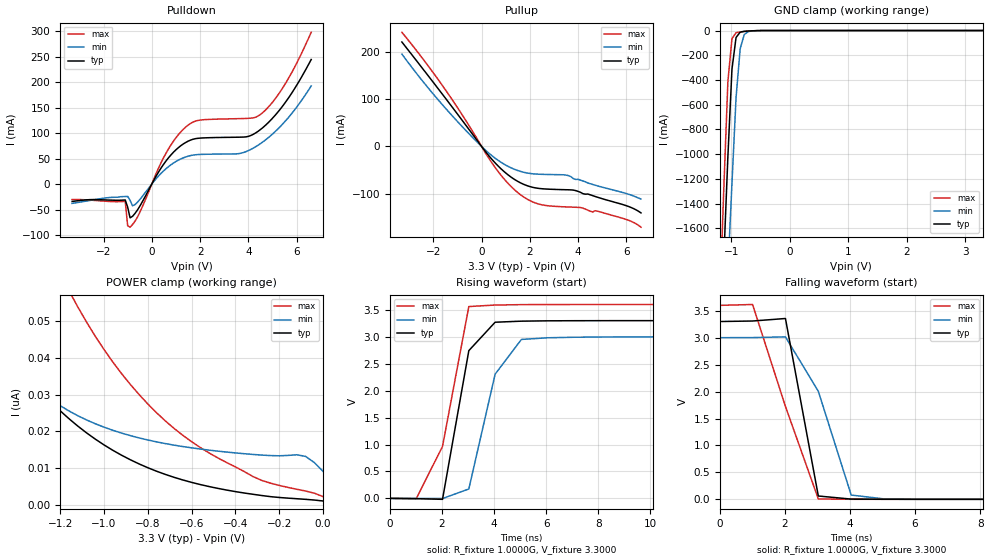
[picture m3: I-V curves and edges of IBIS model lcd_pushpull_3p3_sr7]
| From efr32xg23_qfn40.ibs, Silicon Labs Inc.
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|   Model lcd_pushpull_3p3_sr7
[Model]  lcd_pushpull_3p3_sr7
Model_type 3-state
Polarity   Non-Inverting
Enable   Active-High
C_comp   1.6300pF   1.4000pF   2.7000pF
[Temperature Range]   25.0000   0.1250k   -40.0000
[Pullup Reference]   3.3000V   3.0000V   3.6000V
[Pulldown Reference]   0.0V   0.0V   0.0V
[POWER Clamp Reference]   3.3000V   3.0000V   3.6000V
[GND Clamp Reference]   0.0V   0.0V   0.0V
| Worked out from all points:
|   slope of the pulldown table from 0 to 0.495 V, typ, clamps not added: 12.6 ohm
|   slope of the pullup table from 0 to 0.495 V, typ, clamps not added: 15.9 ohm
|   GND clamp passes 1 mA (typ) near -0.56 V on its own axis
|   rising waveform, R_fixture 1.0000G, V_fixture 3.3000: 20-80 % time 724ps typ, 955ps min, 1ns max; typ from 0 V to 3.3 V
|   falling waveform, R_fixture 1.0000G, V_fixture 3.3000: 20-80 % time 607ps typ, 1.13ns min, 1.21ns max; typ from 3.3 V to 0 V
[Pulldown]
|Voltage   I(typ)   I(min)   I(max)
-3.3V     -34.2mA    -37.99mA   -30.45mA
-1.1V     -31.33mA   -24.53mA   -34.17mA
-1V       -45.32mA   -24.25mA   -81.91mA
-900mV    -66.33mA   -32.01mA   -84.65mA
-700mV    -57.95mA   -40.56mA   -73.32mA
500mV     39.57mA    26.37mA    52.76mA
1.2V      75.23mA    49.28mA    102.4mA
1.9V      89.73mA    57.85mA    124.8mA
3.6V      92mA       59.71mA    128.4mA
4.5V      107.1mA    79.43mA    136.7mA
5.5V      158.4mA    122.1mA    194.8mA
6.6V      244.5mA    192.6mA    297.9mA
[Pullup]
|Voltage   I(typ)   I(min)   I(max)
-3.3V     221.2mA    195.6mA    241.7mA
-1.7V     115.8mA    92.91mA    134.7mA
-200mV    13.9mA     10.19mA    17.6mA
200mV     -13.41mA   -9.668mA   -17.24mA
700mV     -42.19mA   -29.99mA   -54.16mA
1.5V      -74.1mA    -51.07mA   -97.84mA
1.9V      -83.4mA    -56.39mA   -112mA
2.4V      -89.1mA    -58.9mA    -122.5mA
3.6V      -91.86mA   -61.88mA   -128.3mA
4.9V      -109.2mA   -84.97mA   -138.5mA
6.1V      -127.5mA   -101.5mA   -156.7mA
6.6V      -140.8mA   -111.3mA   -171mA
[GND_clamp]
|Voltage   I(typ)   I(min)   I(max)
-3.3V     -27.87A    -25.05A    -30.64A
-1.2V     -2.686A    -3.389A    -2.22A
-1.13V    -1.852A    -2.669A    -1.282A
-1.06V    -1.021A    -1.951A    -413.8mA
-990mV    -311.8mA   -1.235A    -64.72mA
-920mV    -56.25mA   -542.5mA   -17.8mA
-850mV    -13.45mA   -148.5mA   -11.08mA
-780mV    -6.591mA   -32.68mA   -7.457mA
-710mV    -4.029mA   -8.323mA   -4.574mA
-360mV    -18.91uA   -70.05uA   -6.844uA
3.3V      1.07nA     13.64nA    781.9pA
[POWER_clamp]
|Voltage   I(typ)   I(min)   I(max)
-3.28V    727.8nA    32.99uA    1.086uA
-1.6V     57.64nA    55.61nA    128.6nA
-1.56V    53.42nA    50.92nA    120.3nA
-1.4V     38.98nA    37.13nA    91.2nA
-1.16V    23.46nA    25.56nA    58.31nA
-1.12V    21.47nA    24.28nA    53.91nA
-880mV    12.29nA    18.85nA    32.79nA
-640mV    6.783nA    15.87nA    18.92nA
-320mV    2.894nA    13.73nA    7.713nA
-120mV    1.684nA    13.64nA    4.257nA
-80mV     1.52nA     13.19nA    3.779nA
0V        1.07nA     9.091nA    2.25nA
[Ramp]
| variable   typ   min   max
dV/dt_r  1.9770/0.7286n   1.7963/0.9806n   2.1574/0.9973n
dV/dt_f  1.9778/0.6079n   1.7971/1.1326n   2.1582/1.2079n
R_load = 10.0000k
[Rising Waveform]
R_fixture= 1.0000G
V_fixture= 3.3000
V_fixture_min= 3.0000
V_fixture_max= 3.6000
|time   V(typ)   V(min)   V(max)
0s        2.697uV    5.542uV    1.599uV
1.01ns    -5.312mV   -1.811mV   -5.517mV
2.02ns    -17.79mV   -2.837mV   965.3mV
3.03ns    2.743V     174.4mV    3.562V
4.04ns    3.271V     2.307V     3.59V
5.051ns   3.291V     2.951V     3.598V
6.061ns   3.297V     2.982V     3.599V
12.12ns   3.3V       3V         3.6V
100ns     3.3V       3V         3.6V
[Falling Waveform]
R_fixture= 1.0000G
V_fixture= 3.3000
V_fixture_min= 3.0000
V_fixture_max= 3.6000
|time   V(typ)   V(min)   V(max)
0s        3.3V       3V         3.6V
1.01ns    3.309V     3.002V     3.616V
2.02ns    3.356V     3.015V     1.724V
3.03ns    61.74mV    2.005V     6.591mV
4.04ns    4.368mV    79.39mV    1.023mV
5.051ns   1.142mV    8.163mV    253.1uV
100ns     2.749uV    5.589uV    1.558uV
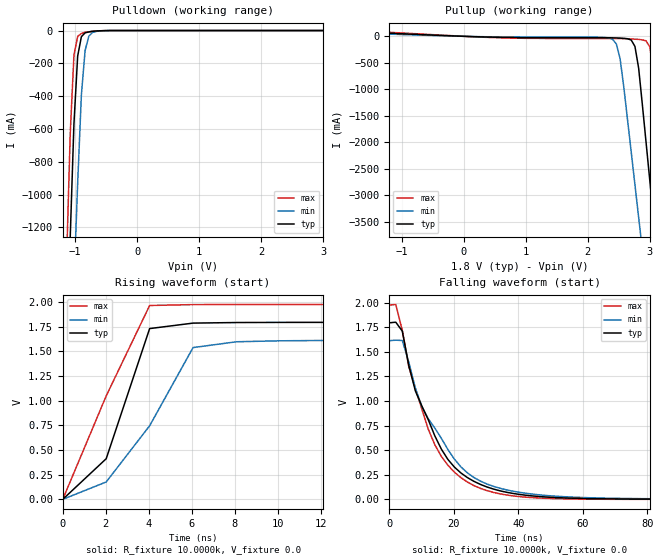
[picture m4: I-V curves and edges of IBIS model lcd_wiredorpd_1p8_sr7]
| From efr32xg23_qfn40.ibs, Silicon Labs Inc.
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|   Model lcd_wiredorpd_1p8_sr7
[Model]  lcd_wiredorpd_1p8_sr7
Model_type Output
Polarity   Non-Inverting
Enable   Active-Low
C_comp   1.6300pF   1.4000pF   2.7000pF
[Temperature Range]   25.0000   0.1250k   -40.0000
[Pullup Reference]   1.8000V   1.6200V   1.9800V
[Pulldown Reference]   0.0V   0.0V   0.0V
[POWER Clamp Reference]   1.8000V   1.6200V   1.9800V
[GND Clamp Reference]   0.0V   0.0V   0.0V
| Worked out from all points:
|   slope of the pulldown table from 0 to 0.27 V, typ, clamps not added: 40.6 kohm
|   slope of the pullup table from 0 to 0.27 V, typ, clamps not added: 26.3 ohm
|   rising waveform, R_fixture 10.0000k, V_fixture 0.0: 20-80 % time 1.83ns typ, 2.89ns min, 2.43ns max; typ from 0 V to 1.79 V
|   falling waveform, R_fixture 10.0000k, V_fixture 0.0: 20-80 % time 13.7ns typ, 15.6ns min, 12.3ns max; typ from 1.8 V to 0 V
[Pulldown]
|Voltage   I(typ)   I(min)   I(max)
-1.8V     -9.867A    -9.569A    -10.32A
-1.14V    -1.973A    -2.773A    -1.419A
-1.08V    -1.26A     -2.157A    -630.5mA
-1.02V    -568mA     -1.543A    -149.7mA
-960mV    -155.8mA   -930mA     -35.75mA
-900mV    -37.31mA   -392mA     -18.18mA
-840mV    -13.93mA   -121.5mA   -10.47mA
-780mV    -8.737mA   -34.04mA   -7.436mA
-720mV    -4.306mA   -11.22mA   -4.934mA
-660mV    -2.722mA   -5.276mA   -2.953mA
-360mV    -27.29uA   -76.51uA   -16.82uA
3.6V      88.26uA    75.14uA    103.4uA
[Pullup]
|Voltage   I(typ)   I(min)   I(max)
-1.8V     89.55mA    65.7mA     113.4mA
2.4V      -28.8mA    -55.09mA   -41.35mA
2.52V     -33.4mA    -414.8mA   -42.59mA
2.76V     -189.9mA   -2.797A    -53.83mA
2.82V     -601mA     -3.414A    -58.12mA
2.94V     -2.006A    -4.65A     -85.78mA
3V        -2.722A    -5.268A    -200.1mA
3.06V     -3.439A    -5.887A    -678.6mA
3.12V     -4.156A    -6.505A    -1.467A
3.24V     -5.593A    -7.743A    -3.079A
3.3V      -6.312A    -8.362A    -3.888A
3.6V      -9.909A    -11.46A    -7.94A
[Ramp]
| variable   typ   min   max
dV/dt_r  1.0772/1.8269n   0.9682/2.8879n   1.1859/2.4307n
dV/dt_f  0.2131/8.5780n   0.1690/11.9028n   0.2652/6.8020n
R_load = 10.0000k
[Rising Waveform]
R_fixture= 10.0000k
V_fixture= 0.0
V_fixture_min= 0.0
V_fixture_max= 0.0
|time   V(typ)   V(min)   V(max)
0s        2.578uV    44.87uV    2.149uV
2.02ns    412mV      176.1mV    1.049V
4.04ns    1.732V     746.3mV    1.966V
6.061ns   1.788V     1.539V     1.975V
8.081ns   1.794V     1.599V     1.976V
10.1ns    1.795V     1.608V     1.976V
200ns     1.795V     1.614V     1.976V
[Falling Waveform]
R_fixture= 10.0000k
V_fixture= 0.0
V_fixture_min= 0.0
V_fixture_max= 0.0
|time   V(typ)   V(min)   V(max)
0s        1.796V     1.614V     1.977V
2.02ns    1.802V     1.619V     1.982V
4.04ns    1.712V     1.616V     1.721V
6.061ns   1.361V     1.396V     1.349V
8.081ns   1.105V     1.133V     1.13V
14.14ns   644.4mV    723.6mV    553.7mV
20.2ns    327.2mV    407.9mV    275.7mV
30.3ns    124.8mV    154.8mV    87.6mV
62.63ns   6.153mV    14.65mV    516.5uV
200ns     -87.28uV   581.6uV    -354.3uV
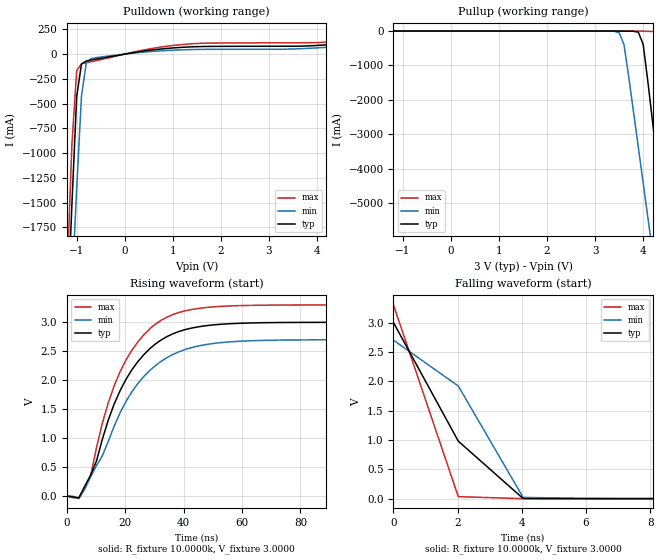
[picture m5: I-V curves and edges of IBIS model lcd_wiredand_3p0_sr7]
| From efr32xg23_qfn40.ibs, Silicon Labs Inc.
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|   Model lcd_wiredand_3p0_sr7
[Model]  lcd_wiredand_3p0_sr7
Model_type Output
Polarity   Inverting
Enable   Active-Low
C_comp   1.6300pF   1.4000pF   2.7000pF
[Temperature Range]   25.0000   0.1250k   -40.0000
[Pullup Reference]   3.0000V   2.7000V   3.3000V
[Pulldown Reference]   0.0V   0.0V   0.0V
[POWER Clamp Reference]   3.0000V   2.7000V   3.3000V
[GND Clamp Reference]   0.0V   0.0V   0.0V
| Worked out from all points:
|   slope of the pulldown table from 0 to 0.45 V, typ, clamps not added: 13.2 ohm
|   rising waveform, R_fixture 10.0000k, V_fixture 3.0000: 20-80 % time 15.6ns typ, 17.9ns min, 14.6ns max; typ from 0.003 V to 3 V
|   falling waveform, R_fixture 10.0000k, V_fixture 3.0000: 20-80 % time 2.2ns typ, 2.09ns min, 1.23ns max; typ from 3 V to 0.003 V
[Pulldown]
|Voltage   I(typ)   I(min)   I(max)
-3V       -24.3A     -21.99A    -26.6A
-1.2V     -2.716A    -3.412A    -2.254A
-1.1V     -1.526A    -2.385A    -915.6mA
-1V       -429.7mA   -1.36A     -165.3mA
-900mV    -99.37mA   -421mA     -98.78mA
-800mV    -69.26mA   -90.62mA   -87.32mA
-700mV    -59.97mA   -45.41mA   -76.82mA
400mV     30.95mA    19.99mA    42.35mA
1.1V      65.5mA     41.43mA    91.79mA
4.2V      93.5mA     68.54mA    121.5mA
5.1V      135.6mA    103.8mA    168.6mA
6V        196.8mA    153.8mA    241.9mA
[Pullup]
|Voltage   I(typ)   I(min)   I(max)
-3V       338.2nA    9.289uA    587.2nA
3.5V      -430.7uA   -50.4mA    -8.469nA
3.6V      -1.559mA   -390.7mA   -692.6nA
4V        -385.8mA   -4.417A    -4.219mA
4.1V      -1.495A    -5.446A    -8.403mA
4.2V      -2.686A    -6.476A    -14.95mA
4.3V      -3.882A    -7.507A    -84.19mA
4.4V      -5.077A    -8.538A    -881.8mA
4.5V      -6.274A    -9.569A    -2.22A
4.7V      -8.669A    -11.63A    -4.917A
4.8V      -9.867A    -12.66A    -6.266A
6V        -24.27A    -25.05A    -22.51A
[Ramp]
| variable   typ   min   max
dV/dt_r  -0.1715m/16.5924p   -0.1952m/52.2320p   -0.1327m/7.4384p
dV/dt_f  1.7980/2.2050n   1.6171/2.0910n   1.9783/1.2251n
R_load = 10.0000k
[Rising Waveform]
R_fixture= 10.0000k
V_fixture= 3.0000
V_fixture_min= 2.7000
V_fixture_max= 3.3000
|time   V(typ)   V(min)   V(max)
0s        3.394mV    4.689mV    2.757mV
4.04ns    -26.64mV   -43.13mV   -32.57mV
8.081ns   361.7mV    335.4mV    354.1mV
14.14ns   1.316V     949.2mV    1.614V
18.18ns   1.821V     1.441V     2.148V
22.22ns   2.182V     1.801V     2.519V
30.3ns    2.627V     2.254V     2.97V
38.38ns   2.842V     2.493V     3.17V
66.67ns   2.992V     2.687V     3.295V
200ns     3V         2.7V       3.3V
[Falling Waveform]
R_fixture= 10.0000k
V_fixture= 3.0000
V_fixture_min= 2.7000
V_fixture_max= 3.3000
|time   V(typ)   V(min)   V(max)
0s        3V         2.7V       3.3V
2.02ns    981.8mV    1.92V      37.65mV
4.04ns    5.833mV    24.8mV     3.331mV
6.061ns   3.703mV    6.836mV    2.832mV
10.1ns    3.446mV    4.884mV    2.783mV
200ns     3.395mV    4.692mV    2.758mV
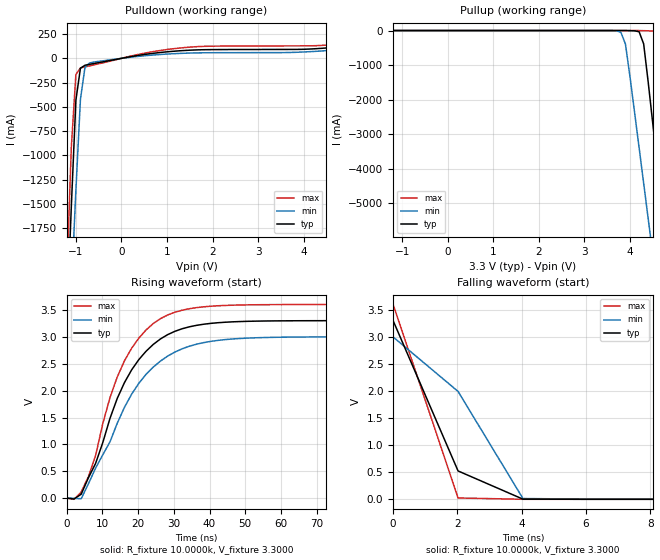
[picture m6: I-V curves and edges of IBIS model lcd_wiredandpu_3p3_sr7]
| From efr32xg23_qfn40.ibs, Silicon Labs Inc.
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|   Model lcd_wiredandpu_3p3_sr7
[Model]  lcd_wiredandpu_3p3_sr7
Model_type Output
Polarity   Inverting
Enable   Active-Low
C_comp   1.6300pF   1.4000pF   2.7000pF
[Temperature Range]   25.0000   0.1250k   -40.0000
[Pullup Reference]   3.3000V   3.0000V   3.6000V
[Pulldown Reference]   0.0V   0.0V   0.0V
[POWER Clamp Reference]   3.3000V   3.0000V   3.6000V
[GND Clamp Reference]   0.0V   0.0V   0.0V
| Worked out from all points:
|   slope of the pulldown table from 0 to 0.495 V, typ, clamps not added: 12.6 ohm
|   slope of the pullup table from 0 to 0.495 V, typ, clamps not added: 40.1 kohm
|   rising waveform, R_fixture 10.0000k, V_fixture 3.3000: 20-80 % time 12.9ns typ, 15.3ns min, 11.5ns max; typ from 0.004 V to 3.3 V
|   falling waveform, R_fixture 10.0000k, V_fixture 3.3000: 20-80 % time 1.44ns typ, 2.24ns min, 1.22ns max; typ from 3.3 V to 0.004 V
[Pulldown]
|Voltage   I(typ)   I(min)   I(max)
-3.3V     -27.9A     -25.09A    -30.67A
-1.2V     -2.717A    -3.413A    -2.255A
-1.1V     -1.526A    -2.386A    -916mA
-1V       -431.1mA   -1.361A    -166.1mA
-900mV    -101.3mA   -422.8mA   -99.6mA
-800mV    -71.14mA   -92.96mA   -88.1mA
-700mV    -61.69mA   -47.63mA   -77.54mA
400mV     32.64mA    21.8mA     43.42mA
1.2V      75.23mA    49.28mA    102.4mA
4.5V      107.1mA    79.44mA    136.7mA
5.5V      158.4mA    122.1mA    194.8mA
6.6V      244.6mA    192.8mA    298mA
[Pullup]
|Voltage   I(typ)   I(min)   I(max)
-3.3V     82.22uA    106.9uA    95.53uA
3.8V      -523.4uA   -50.48mA   -109.5uA
3.9V      -1.654mA   -390.8mA   -113uA
4.3V      -385.9mA   -4.417A    -4.337mA
4.4V      -1.495A    -5.447A    -8.523mA
4.5V      -2.686A    -6.476A    -15.07mA
4.6V      -3.88A     -7.507A    -84.31mA
4.7V      -5.077A    -8.538A    -881.9mA
4.8V      -6.274A    -9.569A    -2.22A
5V        -8.669A    -11.63A    -4.914A
5.1V      -9.868A    -12.66A    -6.266A
6.6V      -27.87A    -28.14A    -26.57A
[Ramp]
| variable   typ   min   max
dV/dt_r  0.3946/12.6592n   0.3211/14.1139n   0.4830/11.4428n
dV/dt_f  1.9778/1.4410n   1.7970/2.2372n   2.1582/1.2206n
R_load = 10.0000k
[Rising Waveform]
R_fixture= 10.0000k
V_fixture= 3.3000
V_fixture_min= 3.0000
V_fixture_max= 3.6000
|time   V(typ)   V(min)   V(max)
0s        3.595mV    4.859mV    2.976mV
4.04ns    75.78mV    -8.601mV   117.1mV
6.061ns   381.4mV    269.2mV    402.1mV
8.081ns   648.4mV    561mV      795mV
12.12ns   1.488V     1.051V     1.875V
18.18ns   2.387V     1.935V     2.789V
24.24ns   2.859V     2.438V     3.247V
32.32ns   3.15V      2.777V     3.494V
56.57ns   3.294V     2.988V     3.597V
200ns     3.3V       3V         3.6V
[Falling Waveform]
R_fixture= 10.0000k
V_fixture= 3.3000
V_fixture_min= 3.0000
V_fixture_max= 3.6000
|time   V(typ)   V(min)   V(max)
0s        3.3V       3V         3.6V
2.02ns    527.1mV    1.995V     28.02mV
4.04ns    6.236mV    17.66mV    3.883mV
10.1ns    3.643mV    5.016mV    3mV
200ns     3.596mV    4.861mV    2.976mV
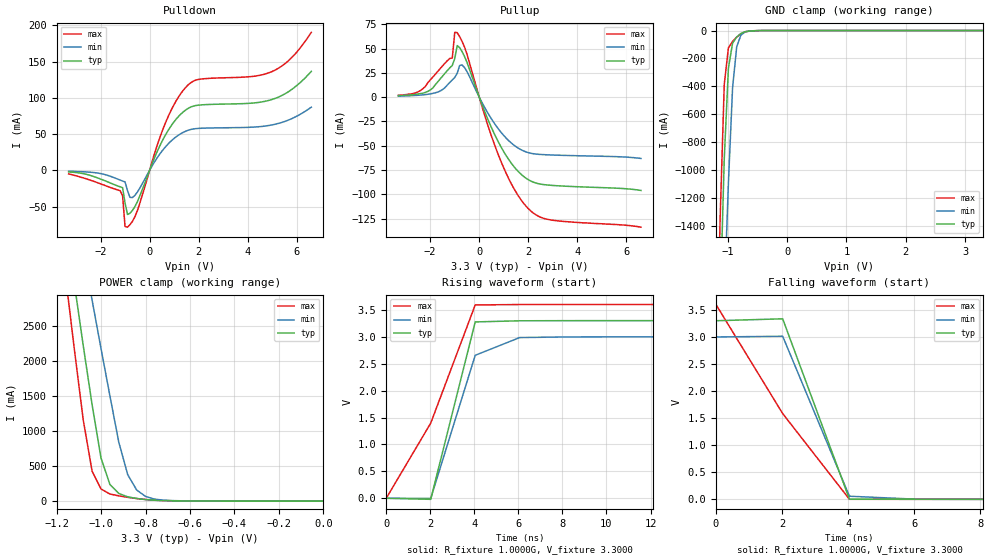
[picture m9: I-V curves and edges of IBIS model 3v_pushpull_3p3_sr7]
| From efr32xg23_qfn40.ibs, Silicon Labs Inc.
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|   Model 3v_pushpull_3p3_sr7
[Model]  3v_pushpull_3p3_sr7
Model_type 3-state
Polarity   Non-Inverting
Enable   Active-High
C_comp   1.6300pF   1.4000pF   2.7000pF
[Temperature Range]   25.0000   0.1250k   -40.0000
[Pullup Reference]   3.3000V   3.0000V   3.6000V
[Pulldown Reference]   0.0V   0.0V   0.0V
[POWER Clamp Reference]   3.3000V   3.0000V   3.6000V
[GND Clamp Reference]   0.0V   0.0V   0.0V
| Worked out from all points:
|   slope of the pulldown table from 0 to 0.495 V, typ, clamps not added: 12.7 ohm
|   slope of the pullup table from 0 to 0.495 V, typ, clamps not added: 15.9 ohm
|   GND clamp passes 1 mA (typ) near -0.52 V on its own axis
|   POWER clamp passes 1 mA (typ) near -0.53 V on its own axis
|   rising waveform, R_fixture 1.0000G, V_fixture 3.3000: 20-80 % time 1.21ns typ, 1.37ns min, 2.34ns max; typ from 0 V to 3.3 V
|   falling waveform, R_fixture 1.0000G, V_fixture 3.3000: 20-80 % time 1.2ns typ, 1.23ns min, 2.4ns max; typ from 3.3 V to 0 V
[Pulldown]
|Voltage   I(typ)   I(min)   I(max)
-3.3V     -2.107mA   -1.127mA   -4.9mA
-1.2V     -22.64mA   -13.29mA   -27.99mA
-1.1V     -23.81mA   -14.62mA   -34.8mA
-1V       -44.79mA   -15.83mA   -77.16mA
-900mV    -60.74mA   -27.73mA   -78.18mA
-800mV    -59.07mA   -37.06mA   -74.82mA
-600mV    -50.02mA   -34.4mA    -64.06mA
700mV     51.87mA    34.37mA    69.6mA
1.5V      83.85mA    54.41mA    115.3mA
5V        97.8mA     62.75mA    136.3mA
5.8V      111.5mA    71.33mA    155.5mA
6.6V      136.5mA    87.15mA    190.3mA
[Pullup]
|Voltage   I(typ)   I(min)   I(max)
-3.3V     1.555mA    1.122mA    1.973mA
-2.5V     3.262mA    1.977mA    5.46mA
-1.9V     9.363mA    3.866mA    20.58mA
-1.1V     32.72mA    17.85mA    40.37mA
-1V       39.81mA    20.25mA    66.83mA
-900mV    53.2mA     24.71mA    66.53mA
-800mV    51.12mA    32.61mA    62.41mA
-600mV    41.88mA    30.52mA    51.53mA
800mV     -47.12mA   -33.35mA   -60.72mA
2V        -84.98mA   -57.12mA   -114.8mA
2.9V      -90.74mA   -59.5mA    -126.4mA
6.6V      -96.11mA   -63.13mA   -133.9mA
[GND_clamp]
|Voltage   I(typ)   I(min)   I(max)
-3.3V     -36.82A    -34.37A    -38.92A
-1.2V     -3.169A    -3.961A    -2.635A
-1.13V    -1.976A    -2.875A    -1.354A
-1.06V    -919.5mA   -1.925A    -386.3mA
-990mV    -269.8mA   -1.092A    -124.2mA
-920mV    -91.07mA   -411.1mA   -78.21mA
-850mV    -46.3mA    -116.2mA   -47.38mA
-780mV    -21.47mA   -33.46mA   -23mA
-710mV    -8.335mA   -10.37mA   -9.191mA
-430mV    -188uA     -421.9uA   -101.6uA
3.3V      1.131nA    22.57uA    998.8pA
[POWER_clamp]
|Voltage   I(typ)   I(min)   I(max)
-3.28V    55.25A     49.02A     61.14A
-1.16V    4.026A     5.102A     3.218A
-1.12V    3.102A     4.316A     2.168A
-1.08V    2.218A     3.57A      1.158A
-1.04V    1.373A     2.863A     426mA
-1V       614.4mA    2.175A     173.2mA
-960mV    237.7mA    1.5A       101.5mA
-920mV    109.2mA    839mA      74.96mA
-880mV    61.4mA     377.7mA    54.07mA
-840mV    37.94mA    159.6mA    37.09mA
-720mV    7.455mA    13.75mA    7.89mA
0V        1.131nA    10.99nA    1.2nA
[Ramp]
| variable   typ   min   max
dV/dt_r  1.9772/1.2143n   1.7964/1.3839n   2.1575/2.3371n
dV/dt_f  1.9778/1.2010n   1.7971/1.2336n   2.1582/2.4028n
R_load = 10.0000k
[Rising Waveform]
R_fixture= 1.0000G
V_fixture= 3.3000
V_fixture_min= 3.0000
V_fixture_max= 3.6000
|time   V(typ)   V(min)   V(max)
0s        1.043uV    2.109uV    615.4nV
2.02ns    -19.64mV   -2.852mV   1.396V
4.04ns    3.276V     2.656V     3.591V
6.061ns   3.297V     2.986V     3.599V
8.081ns   3.3V       2.997V     3.6V
200ns     3.3V       3V         3.6V
[Falling Waveform]
R_fixture= 1.0000G
V_fixture= 3.3000
V_fixture_min= 3.0000
V_fixture_max= 3.6000
|time   V(typ)   V(min)   V(max)
0s        3.3V       3V         3.6V
2.02ns    3.336V     3.013V     1.585V
4.04ns    4.485mV    57.28mV    1.112mV
6.061ns   394uV      2.606mV    84.17uV
8.081ns   77.37uV    520.2uV    25.22uV
200ns     1.044uV    2.202uV    599.2nV
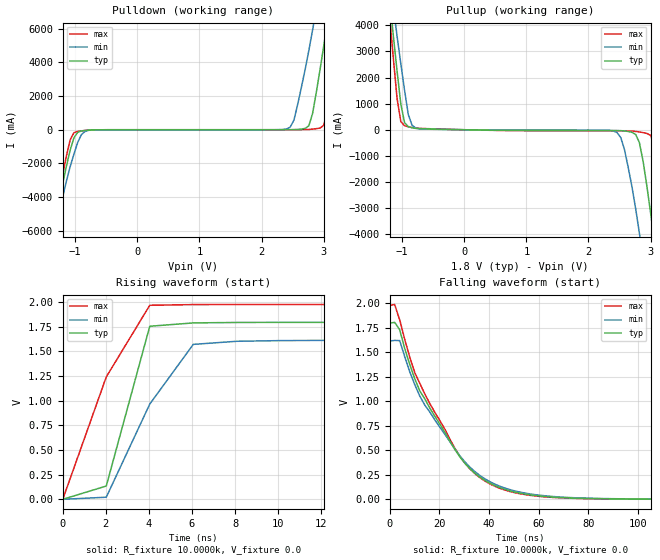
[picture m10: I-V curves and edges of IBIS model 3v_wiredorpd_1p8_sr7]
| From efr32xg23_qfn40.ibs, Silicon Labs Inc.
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|   Model 3v_wiredorpd_1p8_sr7
[Model]  3v_wiredorpd_1p8_sr7
Model_type Output
Polarity   Non-Inverting
Enable   Active-Low
C_comp   1.6300pF   1.4000pF   2.7000pF
[Temperature Range]   25.0000   0.1250k   -40.0000
[Pullup Reference]   1.8000V   1.6200V   1.9800V
[Pulldown Reference]   0.0V   0.0V   0.0V
[POWER Clamp Reference]   1.8000V   1.6200V   1.9800V
[GND Clamp Reference]   0.0V   0.0V   0.0V
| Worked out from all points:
|   slope of the pulldown table from 0 to 0.27 V, typ, clamps not added: 44.9 kohm
|   slope of the pullup table from 0 to 0.27 V, typ, clamps not added: 26.3 ohm
|   rising waveform, R_fixture 10.0000k, V_fixture 0.0: 20-80 % time 1.34ns typ, 2.46ns min, 2.32ns max; typ from 0 V to 1.8 V
|   falling waveform, R_fixture 10.0000k, V_fixture 0.0: 20-80 % time 23.3ns typ, 24.3ns min, 22.9ns max; typ from 1.8 V to 0.001 V
[Pulldown]
|Voltage   I(typ)   I(min)   I(max)
-1.8V     -14.24A    -14.11A    -14.46A
-1.38V    -6.468A    -6.98A     -6.16A
-1.14V    -2.14A     -3.023A    -1.532A
-1.02V    -472.4mA   -1.439A    -175.3mA
-780mV    -21.14mA   -32.29mA   -22.9mA
2.46V     4.055mA    156.9mA    301.8uA
2.76V     235.9mA    4.702A     17.88mA
2.82V     958.6mA    5.911A     36.7mA
2.94V     3.56A      8.545A     100.9mA
3.06V     6.47A      11.36A     1.157A
3.24V     11.25A     15.63A     5.98A
3.6V      20.85A     23.6A      16.79A
[Pullup]
|Voltage   I(typ)   I(min)   I(max)
-1.8V     20.86A     19.71A     22.08A
-1.2V     4.996A     5.919A     4.326A
-1.08V    2.239A     3.576A     1.188A
-960mV    270.1mA    1.509A     153.5mA
-840mV    73.79mA    176mA      86.18mA
-720mV    40.46mA    33.96mA    52.78mA
2.46V     -30.6mA    -110.1mA   -41.67mA
2.58V     -47.09mA   -768.5mA   -43.99mA
2.82V     -498.4mA   -3.974A    -84.68mA
3V        -3.194A    -6.995A    -216.9mA
3.24V     -7.63A     -11.15A    -3.824A
3.6V      -14.27A    -16.88A    -11.03A
[Ramp]
| variable   typ   min   max
dV/dt_r  1.0775/1.3429n   0.9686/2.4598n   1.1861/2.3207n
dV/dt_f  0.1964/25.9671n   0.1553/27.7005n   0.2452/24.5618n
R_load = 10.0000k
[Rising Waveform]
R_fixture= 10.0000k
V_fixture= 0.0
V_fixture_min= 0.0
V_fixture_max= 0.0
|time   V(typ)   V(min)   V(max)
0s        4.6uV      60.57uV    4.524uV
2.02ns    135.1mV    21.47mV    1.242V
4.04ns    1.756V     966.6mV    1.969V
6.061ns   1.79V      1.572V     1.976V
8.081ns   1.794V     1.604V     1.977V
10.1ns    1.796V     1.61V      1.977V
200ns     1.796V     1.614V     1.977V
[Falling Waveform]
R_fixture= 10.0000k
V_fixture= 0.0
V_fixture_min= 0.0
V_fixture_max= 0.0
|time   V(typ)   V(min)   V(max)
0s        1.796V     1.614V     1.977V
2.02ns    1.804V     1.62V      1.986V
4.04ns    1.729V     1.618V     1.831V
10.1ns    1.23V      1.17V      1.291V
14.14ns   1.025V     961.3mV    1.074V
26.26ns   508mV      513.2mV    519.7mV
34.34ns   266.1mV    282.1mV    262.1mV
44.44ns   119mV      133mV      111.9mV
76.77ns   10.96mV    14.39mV    8.929mV
200ns     728.2uV    1.013mV    567.9uV
